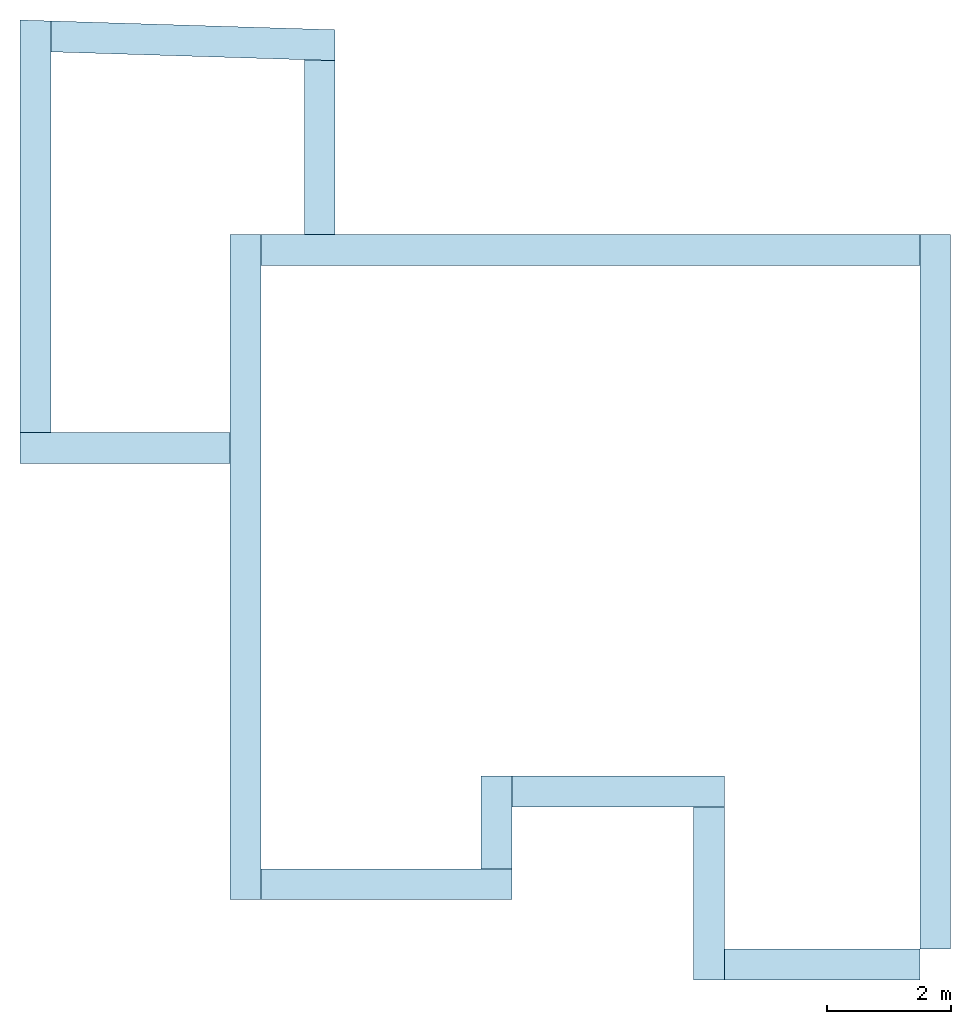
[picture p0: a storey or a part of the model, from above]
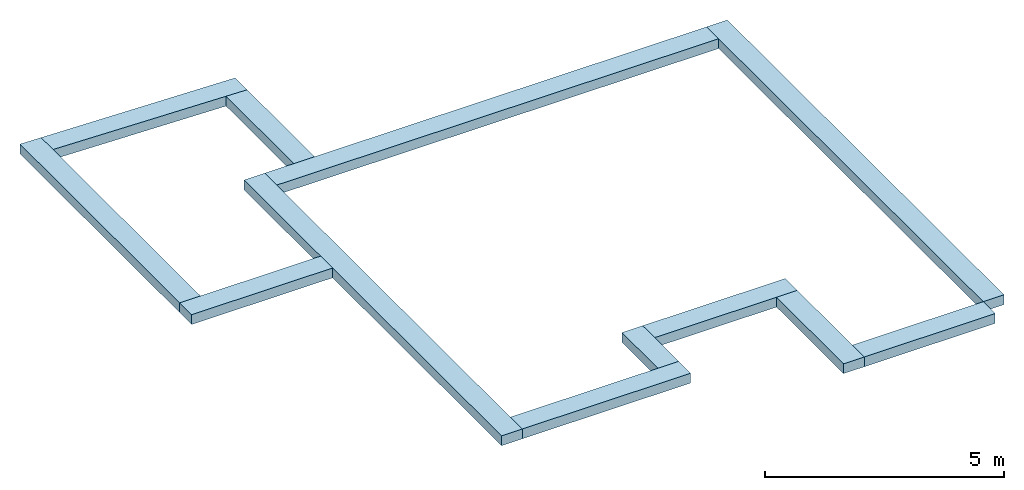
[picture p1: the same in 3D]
Properties of the parts of a building model (IFC2X3)

# File
Description: ViewDefinition [CoordinationView_V2.0], RevitIdentifiers [VersionGUID: 436fcdb2-af28-421d-9099-26dd50524c73, NumberOfSaves: 48], CoordinateReference [CoordinateBase: Coordonnées partagées]
File name: Numéro du projet
Time: 2023-03-24T09:25:57+01:00
Written by: ODA SDAI 22.12
Made in: 23.1.10.4 - Exporter 23.2.2.0 - Interface utilisateur alternative 23.2.2.0

# IfcProject, Numéro du projet
LongName: Nom du projet; Phase: Etat du projet

# IfcSite, Default
RefLatitude: 48, 51, 23, 999633; RefLongitude: 2, 21, 3, 553905; RefElevation: 0 cm

# IfcBuilding
Pset_BuildingCommon - NumberOfStoreys: 7

# IfcBuildingStorey: Niveau:Ligne du Niveau (7)
Name | LongName | Elevation (cm)
0_Fond de fouille | 0_Fond de fouille | -95
0_Fondation | 0_Fondation | -70
0_-0.13 | 0_-0.13 | -13
1_Rez-de-chaussée | 1_Rez-de-chaussée | 0
x_Arase étanchéité | x_Arase étanchéité | 290
X_Arase garage | X_Arase garage | 307
x_Arase habitation | x_Arase habitation | 350

# IfcSpace: Bunderie 1:278772, 1
In: 1_Rez-de-chaussée
LongName: Bunderie; InteriorOrExteriorSpace: INTERNAL
Pset_SpaceCommon - Reference: Bunderie 1

# IfcSpace: Chambre 1 6:278787, 6
In: 1_Rez-de-chaussée
LongName: Chambre 1; InteriorOrExteriorSpace: INTERNAL
Pset_SpaceCommon - Reference: Chambre 1 6

# IfcSpace: Chambre 2 3:278778, 3
In: 1_Rez-de-chaussée
LongName: Chambre 2; InteriorOrExteriorSpace: INTERNAL
Pset_SpaceCommon - Reference: Chambre 2 3

# IfcSpace: Chambre 3 2:278775, 2
In: 1_Rez-de-chaussée
LongName: Chambre 3; InteriorOrExteriorSpace: INTERNAL
Pset_SpaceCommon - Reference: Chambre 3 2

# IfcSpace: Dégagement 8:278966, 8
In: 1_Rez-de-chaussée
LongName: Dégagement; InteriorOrExteriorSpace: INTERNAL
Pset_SpaceCommon - Reference: Dégagement 8

# IfcSpace: Garage 9:278980, 9
In: 1_Rez-de-chaussée
LongName: Garage; InteriorOrExteriorSpace: INTERNAL
Pset_SpaceCommon - Reference: Garage 9

# IfcSpace: PL 1 12:278989, 12
In: 1_Rez-de-chaussée
LongName: PL 1; InteriorOrExteriorSpace: INTERNAL
Pset_SpaceCommon - Reference: PL 1 12

# IfcSpace: PL 13:278999, 13
In: 1_Rez-de-chaussée
LongName: PL; InteriorOrExteriorSpace: INTERNAL
Pset_SpaceCommon - Reference: PL 13

# IfcSpace: PL 2 10:278983, 10
In: 1_Rez-de-chaussée
LongName: PL 2; InteriorOrExteriorSpace: INTERNAL
Pset_SpaceCommon - Reference: PL 2 10

# IfcSpace: PL 3 11:278986, 11
In: 1_Rez-de-chaussée
LongName: PL 3; InteriorOrExteriorSpace: INTERNAL
Pset_SpaceCommon - Reference: PL 3 11

# IfcSpace: Salle d'eau 5:278784, 5
In: 1_Rez-de-chaussée
LongName: Salle d'eau; InteriorOrExteriorSpace: INTERNAL
Pset_SpaceCommon - Reference: Salle d'eau 5

# IfcSpace: WC 4:278781, 4
In: 1_Rez-de-chaussée
LongName: WC; InteriorOrExteriorSpace: INTERNAL
Pset_SpaceCommon - Reference: WC 4

# IfcColumn: Poteau rectangulaire:150 x 150 mm (2)
In: 0_Fondation
Type - PredefinedType: COLUMN; Material: <Unnamed>
Type - Pset_ColumnCommon - IsExternal: no; LoadBearing: yes
Pset_ColumnCommon - Reference: 150 x 150 mm
Pset_QuantityTakeOff - Reference: 150 x 150 mm; sets with these values: 2
Name (Poteau rectangulaire:150 x 150 mm:...)
244132
244292

# IfcCovering: Plafond de base:Plafond 600 mm x 1200 mm, Plafond de base:Plafond 600 mm x 1200 mm:302400
In: 1_Rez-de-chaussée
Type - PredefinedType: CEILING
Pset_CoveringCommon - Reference: Plafond 600 mm x 1200 mm; sets with these values: 2

# IfcDoor: Ext. Simple:Vitrée haut - 0.80 m x 2.00 m, Ext. Simple:Vitrée haut - 0.80 m x 2.00 m:292498
In: 1_Rez-de-chaussée
Type - OperationType: SINGLE_SWING_LEFT; ParameterTakesPrecedence: no; Sizeable: no; Material: PVC - Blanc, Verre
Type - Ext. Simple:Vitrée haut - 0.80 m x 2.00 m:292498:1 - PanelOperation: SWINGING
Type - Pset_DoorCommon - IsExternal: yes; ThermalTransmittance: 5.5617 kg/K/s3
OverallHeight: 205 cm; OverallWidth: 90 cm
Pset_DoorCommon - Reference: Vitrée haut - 0.80 m x 2.00 m
Pset_QuantityTakeOff - Reference: Vitrée haut - 0.80 m x 2.00 m

# IfcDoor: Garage sectionnelle:240 x 200, Garage sectionnelle:240 x 200:256978
In: 1_Rez-de-chaussée
Type - OperationType: ROLLINGUP; ParameterTakesPrecedence: no; Sizeable: no; Material: Plastique - Noir, Peinture - Grise, Verre
Type - Garage sectionnelle:240 x 200:256978:1 - PanelOperation: ROLLINGUP
Type - Pset_DoorCommon - IsExternal: yes
OverallHeight: 201.5 cm; OverallWidth: 243 cm
Pset_DoorCommon - Reference: 240 x 200
Pset_QuantityTakeOff - Reference: 240 x 200

# IfcDoor: Int. Simple:PP (0.83m x 2.04m) (7)
In: 1_Rez-de-chaussée
Type - ParameterTakesPrecedence: no; Sizeable: no; Material: Finition Peinture - Blanc satiné, Bois - Panneau de porte, Bois - Cadre de porte
Type - Pset_DoorCommon - IsExternal: no; ThermalTransmittance: 3.7021 kg/K/s3
OverallHeight: 207.5 cm; OverallWidth: 90 cm
Pset_DoorCommon - Reference: PP (0.83m x 2.04m)
Pset_QuantityTakeOff - Reference: PP (0.83m x 2.04m)
Name (Int. Simple:PP (0.83m x 2.04m):...)
276797
276835
276865
276890
276915
276942
296157

# IfcDoor: Placard coulissante - 2 panneaux:PL coulissante - 2 panneaux 134/250, Placard coulissante - 2 panneaux:PL coulissante - 2 panneaux 134/250:278358
In: 1_Rez-de-chaussée
Type - OperationType: SLIDING_TO_RIGHT; ParameterTakesPrecedence: no; Sizeable: no; Material: Placard - Profil, Placard - Encadrement, Placard - Porte
Type - Placard coulissante - 2 panneaux:PL coulissante - 2 panneaux 134/250:278358:1 - PanelOperation: SLIDING
Type - Pset_DoorCommon - IsExternal: no; ThermalTransmittance: 3.7021 kg/K/s3
OverallHeight: 250 cm; OverallWidth: 134 cm
Pset_DoorCommon - Reference: PL coulissante - 2 panneaux 134/250
Pset_QuantityTakeOff - Reference: PL coulissante - 2 panneaux 134/250

# IfcDoor: Placard coulissante - 2 panneaux:PL coulissante - 2 panneaux 146/250, Placard coulissante - 2 panneaux:PL coulissante - 2 panneaux 146/250:278236
In: 1_Rez-de-chaussée
Type - OperationType: SLIDING_TO_RIGHT; ParameterTakesPrecedence: no; Sizeable: no; Material: Placard - Profil, Placard - Encadrement, Placard - Porte
Type - Placard coulissante - 2 panneaux:PL coulissante - 2 panneaux 146/250:278236:1 - PanelOperation: SLIDING
Type - Pset_DoorCommon - IsExternal: no; ThermalTransmittance: 3.7021 kg/K/s3
OverallHeight: 250 cm; OverallWidth: 146 cm
Pset_DoorCommon - Reference: PL coulissante - 2 panneaux 146/250
Pset_QuantityTakeOff - Reference: PL coulissante - 2 panneaux 146/250

# IfcDoor: Placard coulissante - 2 panneaux:PL coulissante - 2 panneaux 170/250, Placard coulissante - 2 panneaux:PL coulissante - 2 panneaux 170/250:278422
In: 1_Rez-de-chaussée
Type - OperationType: SLIDING_TO_RIGHT; ParameterTakesPrecedence: no; Sizeable: no; Material: Placard - Profil, Placard - Encadrement, Placard - Porte
Type - Placard coulissante - 2 panneaux:PL coulissante - 2 panneaux 170/250:278422:1 - PanelOperation: SLIDING
Type - Pset_DoorCommon - IsExternal: no; ThermalTransmittance: 3.7021 kg/K/s3
OverallHeight: 250 cm; OverallWidth: 170 cm
Pset_DoorCommon - Reference: PL coulissante - 2 panneaux 170/250
Pset_QuantityTakeOff - Reference: PL coulissante - 2 panneaux 170/250

# IfcDoor: Porte d'entrée gris:90 x 215 cm, Porte d'entrée gris:90 x 215 cm:252917
In: 1_Rez-de-chaussée
Type - ParameterTakesPrecedence: no; Sizeable: no; Material: Zinc, Wood, Cherry - Grain Vertical
Type - Pset_DoorCommon - IsExternal: no
Type - Pset_ManufacturerTypeInformation - Manufacturer: Karona , Inc.
OverallHeight: 218.81 cm; OverallWidth: 97.62 cm; Classification: B2030130 Uniformat (Uniformat)
Pset_DoorCommon - Reference: 90 x 215 cm
Pset_QuantityTakeOff - Reference: 90 x 215 cm

# IfcFooting: Semelle filante:Soubassement 20 cm/ 50 cm x 25 cm (12)
In: 0_Fond de fouille
PredefinedType: STRIP_FOOTING; Material: Béton, haute résistance
Pset_QuantityTakeOff - Reference: Soubassement 20 cm/ 50 cm x 25 cm; sets with these values: 3
Name (Semelle filante:Soubassement 20 cm/ 50 cm x 25 cm:...)
262636
262650
262664
262678
262692
262706
262720
262734
262748
262762
262772
262786

# IfcOpeningElement: Opening (25)
Name | In
Mur de base:Mur extérieur 36cm:242152 | 0_-0.13 | Pset_OpeningElementCommon - Reference: PL coulissante - 2 panneaux 170/250; sets with these values: 2
Mur de base:Mur extérieur 36cm:242231 | 0_-0.13 | Pset_OpeningElementCommon - Reference: PL coulissante - 2 panneaux 146/250; sets with these values: 2
Sol:Dallage partie habitation:257989:2 | 1_Rez-de-chaussée | Pset_OpeningElementCommon - Reference: Dallage partie habitation; sets with these values: 2
Sol:Dallage partie habitation:257989:3 | 1_Rez-de-chaussée | Pset_OpeningElementCommon - Reference: Dallage partie habitation; sets with these values: 2
Mur de base:Mur extérieur 36cm:269685 | 0_-0.13 | Pset_OpeningElementCommon - Reference: Mur extérieur 36cm; sets with these values: 2
Mur de base:Mur extérieur 36cm:269685 | 0_-0.13 | Pset_OpeningElementCommon - Reference: PL coulissante - 2 panneaux 170/250; sets with these values: 2
Mur de base:Int. plâtre 70 mm:275324 | 1_Rez-de-chaussée | Pset_OpeningElementCommon - Reference: PL coulissante - 2 panneaux 170/250; sets with these values: 2
Mur de base:Mur extérieur 22cm:241015 | 0_-0.13
Mur de base:Mur extérieur 36cm:241676 | 0_-0.13
Mur de base:Mur extérieur 36cm:242042 | 0_-0.13
3 x Mur de base:Mur extérieur 36cm:242231 | 0_-0.13
Mur de base:Mur extérieur 22cm:242305 | 0_-0.13
Porte d'entrée gris:90 x 215 cm:252917:1 | 0_-0.13
Int. Simple:PP (0.83m x 2.04m):276797:1 | 1_Rez-de-chaussée
Placard coulissante - 2 panneaux:PL coulissante - 2 panneaux 134/250:278358:1 | 1_Rez-de-chaussée
Placard coulissante - 2 panneaux:PL coulissante - 2 panneaux 146/250:278236:1 | 1_Rez-de-chaussée
Int. Simple:PP (0.83m x 2.04m):276835:1 | 1_Rez-de-chaussée
Int. Simple:PP (0.83m x 2.04m):276865:1 | 1_Rez-de-chaussée
Int. Simple:PP (0.83m x 2.04m):276890:1 | 1_Rez-de-chaussée
Int. Simple:PP (0.83m x 2.04m):276915:1 | 1_Rez-de-chaussée
Placard coulissante - 2 panneaux:PL coulissante - 2 panneaux 170/250:278422:1 | 1_Rez-de-chaussée
Int. Simple:PP (0.83m x 2.04m):276942:1 | 0_-0.13
Int. Simple:PP (0.83m x 2.04m):296157:1 | 1_Rez-de-chaussée

# IfcRoof: Toit de base:Toit ardoise - 100 mm, Toit de base:Toit ardoise - 100 mm:272346
In: x_Arase habitation
Material: Ardoise 10 cm
Pset_QuantityTakeOff - Reference: Toit ardoise - 100 mm
Pset_RoofCommon - IsExternal: yes; Reference: Toit ardoise - 100 mm; ProjectedArea: 112.32 m2; TotalArea: 137.117 m2

# IfcRoof: Toit de base:Toit plat - 100 mm (3)
Material: Asphalte, bitume(1) 10 cm
Pset_QuantityTakeOff - Reference: Toit plat - 100 mm
Pset_RoofCommon - IsExternal: yes; Reference: Toit plat - 100 mm
Name (Toit de base:Toit plat - 100 mm:...) | In | ProjectedArea (m2) | TotalArea (m2)
271285 | x_Arase étanchéité | 11.7 | 11.7065
271880 | x_Arase étanchéité | 7.31 | 7.31406
272552 | X_Arase garage | 24.2091 | 24.2684

# IfcSlab: Base rectangulaire:450mm x 450mm x 250mm (2)
In: 0_Fondation
Type - PredefinedType: BASESLAB; Material: Béton - Béton coulé sur place
Type - Pset_SlabCommon - IsExternal: no
Pset_QuantityTakeOff - Reference: 450mm x 450mm x 250mm; sets with these values: 2
Pset_SlabCommon - Reference: 450mm x 450mm x 250mm
Name (Base rectangulaire:450mm x 450mm x 250mm:...)
265019
265124

# IfcSlab: Sol:Dallage partie garage, Sol:Dallage partie garage:257184
In: 1_Rez-de-chaussée
Type - PredefinedType: FLOOR; Material: Maçonnerie - Béton 12 cm, Terre 15 cm
Type - Pset_SlabCommon - IsExternal: no; ThermalTransmittance: 5.58 kg/K/s3
Pset_QuantityTakeOff - Reference: Dallage partie garage; sets with these values: 2
Pset_SlabCommon - LoadBearing: no; Reference: Dallage partie garage; PitchAngle: 0 deg

# IfcSlab: Sol:Dallage partie habitation, Sol:Dallage partie habitation:257989
In: 1_Rez-de-chaussée
Type - PredefinedType: FLOOR; Material: Maçonnerie - Béton 12 cm, Isolant rigide 10 cm, Sable 5 cm, Gravier 12 cm
Type - Pset_SlabCommon - IsExternal: no; ThermalTransmittance: 0.299425 kg/K/s3
Pset_QuantityTakeOff - Reference: Dallage partie habitation; sets with these values: 2
Pset_SlabCommon - LoadBearing: no; PitchAngle: 0 deg; Reference: Dallage partie habitation

# IfcSlab: Toit de base:Toit ardoise - 100 mm (4)
In: x_Arase habitation
Type - PredefinedType: ROOF
Type - Pset_SlabCommon - IsExternal: yes; ThermalTransmittance: 18.83 kg/K/s3
Material: Ardoise 10 cm
Pset_QuantityTakeOff - Reference: Toit ardoise - 100 mm; sets with these values: 2
Pset_SlabCommon - Reference: Toit ardoise - 100 mm; PitchAngle: 35 deg

# IfcSlab: Toit de base:Toit plat - 100 mm (3)
Type - PredefinedType: ROOF
Type - Pset_SlabCommon - IsExternal: yes; ThermalTransmittance: 11.5 kg/K/s3
Material: Asphalte, bitume(1) 10 cm
Pset_QuantityTakeOff - Reference: Toit plat - 100 mm; sets with these values: 2
Pset_SlabCommon - Reference: Toit plat - 100 mm
Name (Toit de base:Toit plat - 100 mm:...) | In | PitchAngle (deg)
271285 | x_Arase étanchéité | 1.90915
271880 | x_Arase étanchéité | 1.90915
272552 | X_Arase garage | 4.00417

# IfcWall: Mur de base:Mur extérieur 36cm (4)
Type - PredefinedType: STANDARD; Material: Maçonnerie - Enduit 2 cm, Maçonnerie - Béton 20 cm, Mur par défaut 14 cm
Type - Pset_WallCommon - IsExternal: yes
Pset_QuantityTakeOff - Reference: Mur extérieur 36cm; sets with these values: 2
Pset_WallCommon - Reference: Mur extérieur 36cm; ExtendToStructure: no
Name (Mur de base:Mur extérieur 36cm:...) | In | LoadBearing
240888 | 0_-0.13 | no
241851 | 0_-0.13 | no
268756 | x_Arase étanchéité | yes
269143 | x_Arase étanchéité | yes

# IfcWallStandardCase: Mur de base:Int. plâtre 70 mm (16)
In: 1_Rez-de-chaussée
Type - PredefinedType: STANDARD; Material: Mur par défaut 7 cm
Type - Pset_WallCommon - IsExternal: no
Pset_QuantityTakeOff - Reference: Int. plâtre 70 mm; sets with these values: 2
Pset_WallCommon - ExtendToStructure: no; LoadBearing: no; Reference: Int. plâtre 70 mm
Name (Mur de base:Int. plâtre 70 mm:...)
273742
273854
273977
274577
274693
274787
274892
274978
275083
275146
275277
275324
275390
275729
276185
296092

# IfcWallStandardCase: Mur de base:Mur extérieur 22cm (4)
In: 0_-0.13
Type - PredefinedType: STANDARD; Material: Maçonnerie - Enduit 2 cm, Maçonnerie - Béton 20 cm
Type - Pset_WallCommon - IsExternal: yes
Pset_QuantityTakeOff - Reference: Mur extérieur 22cm; sets with these values: 2
Pset_WallCommon - ExtendToStructure: no; LoadBearing: no; Reference: Mur extérieur 22cm
Name (Mur de base:Mur extérieur 22cm:...)
241015
241111
242305
242390

# IfcWallStandardCase: Mur de base:Mur extérieur 36cm (8)
In: 0_-0.13
Type - PredefinedType: STANDARD; Material: Maçonnerie - Enduit 2 cm, Maçonnerie - Béton 20 cm, Mur par défaut 14 cm
Type - Pset_WallCommon - IsExternal: yes
Pset_QuantityTakeOff - Reference: Mur extérieur 36cm; sets with these values: 2
Pset_WallCommon - Reference: Mur extérieur 36cm
Name (Mur de base:Mur extérieur 36cm:...) | LoadBearing | ExtendToStructure
241676 | no | yes
241795 | no | yes
241946 | no | yes
242042 | no | yes
242152 | no | no
242231 | no | no
269685 | yes | yes
269982 | no | yes

# IfcWallStandardCase: Mur de base:Mur soubassement 20 (12)
In: 0_Fondation
Type - PredefinedType: STANDARD; Material: Maçonnerie - Béton(1) 20 cm
Type - Pset_WallCommon - IsExternal: yes
Pset_QuantityTakeOff - Reference: Mur soubassement 20; sets with these values: 2
Pset_WallCommon - ExtendToStructure: no; LoadBearing: no; Reference: Mur soubassement 20
Name (Mur de base:Mur soubassement 20:...)
260673
260869
261010
261122
261220
261301
261409
261627
262150
262320
262450
262562

# IfcWindow: 1 Vantail - Droit:0.60 m x 2.15 m, 1 Vantail - Droit:0.60 m x 2.15 m:245660
In: 1_Rez-de-chaussée
Type - ParameterTakesPrecedence: no; Sizeable: no; Material: Fenêtre - Poignée, Fenêtre - Appui, Fenêtre - Vitrage, Fenêtre - Cadre
Type - Pset_WindowCommon - IsExternal: no
OverallHeight: 228 cm; OverallWidth: 70 cm
Pset_QuantityTakeOff - Reference: 0.60 m x 2.15 m
Pset_WindowCommon - IsExternal: yes; Reference: 0.60 m x 2.15 m

# IfcWindow: 1 Vantail - Droit:0.90 m x 0.95 m, 1 Vantail - Droit:0.90 m x 0.95 m:245599
In: 1_Rez-de-chaussée
Type - ParameterTakesPrecedence: no; Sizeable: no; Material: Fenêtre - Poignée, Fenêtre - Appui, Fenêtre - Vitrage, Fenêtre - Cadre
Type - Pset_WindowCommon - IsExternal: no
OverallHeight: 108 cm; OverallWidth: 100 cm
Pset_QuantityTakeOff - Reference: 0.90 m x 0.95 m
Pset_WindowCommon - IsExternal: yes; Reference: 0.90 m x 0.95 m

# IfcWindow: 1 Vantail - Droit:0.90 m x 1.25 m (3)
In: 1_Rez-de-chaussée
Type - ParameterTakesPrecedence: no; Sizeable: no; Material: Fenêtre - Poignée, Fenêtre - Appui, Fenêtre - Vitrage, Fenêtre - Cadre
Type - Pset_WindowCommon - IsExternal: no
OverallHeight: 138 cm; OverallWidth: 100 cm
Pset_QuantityTakeOff - Reference: 0.90 m x 1.25 m
Pset_WindowCommon - Reference: 0.90 m x 1.25 m
Name (1 Vantail - Droit:0.90 m x 1.25 m:...)
245429 | Pset_WindowCommon - IsExternal: yes
245491
245548

# IfcWindow: PF 2 vantaux coulissants:180 x 215 cm 2 (2)
In: 1_Rez-de-chaussée
Type - OperationType: DOUBLE_PANEL_VERTICAL; ParameterTakesPrecedence: no; Sizeable: no; Material: Fenêtre - Vitrage, Fenêtre - Cadre
Type - Pset_WindowCommon - IsExternal: no
OverallHeight: 224.023 cm; OverallWidth: 190 cm
Pset_QuantityTakeOff - Reference: 180 x 215 cm 2
Pset_WindowCommon - Reference: 180 x 215 cm 2
Name (PF 2 vantaux coulissants:180 x 215 cm 2:...)
248482 | Pset_WindowCommon - IsExternal: yes
248581
